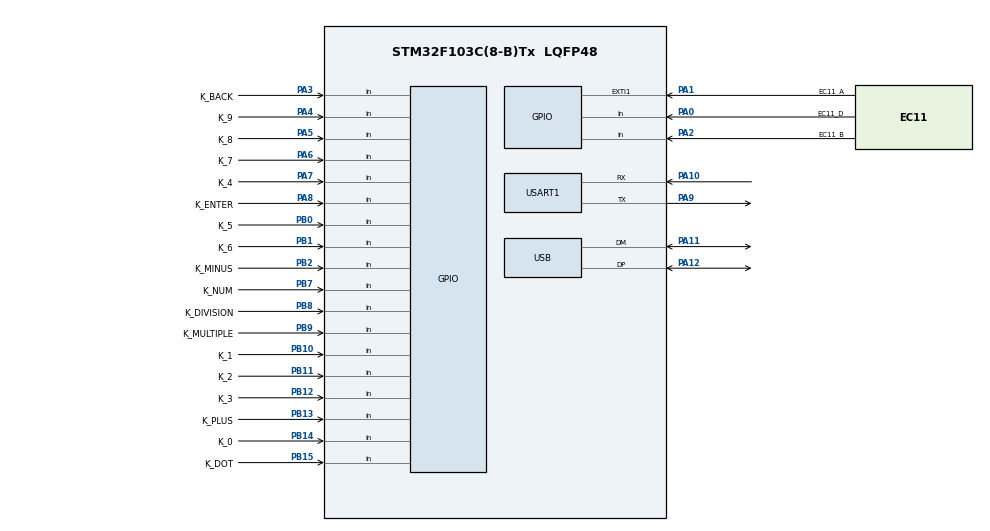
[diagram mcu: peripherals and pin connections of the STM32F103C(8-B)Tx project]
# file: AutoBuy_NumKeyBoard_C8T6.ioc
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Mcu.Family=STM32F1
Mcu.Name=STM32F103C(8-B)Tx
Mcu.Package=LQFP48
NVIC.PriorityGroup=NVIC_PRIORITYGROUP_4
NVIC.USART1_IRQn=true\:0\:0\:false\:false\:true\:true\:true\:true
NVIC.USB_LP_CAN1_RX0_IRQn=true\:0\:0\:false\:false\:true\:false\:true\:true
PA0-WKUP.GPIO_Label=EC11_D
PA0-WKUP.GPIO_PuPd=GPIO_PULLUP
PA0-WKUP.Signal=GPIO_Input
PA1.GPIO_Label=EC11_A
PA1.GPIO_ModeDefaultEXTI=GPIO_MODE_EVT_FALLING
PA1.GPIO_PuPd=GPIO_PULLUP
PA1.Signal=GPXTI1
PA10.Mode=Asynchronous
PA10.Signal=USART1_RX
PA11.Mode=Device
PA11.Signal=USB_DM
PA12.Mode=Device
PA12.Signal=USB_DP
PA13.Mode=Serial_Wire
PA13.Signal=SYS_JTMS-SWDIO
PA14.Mode=Serial_Wire
PA14.Signal=SYS_JTCK-SWCLK
PA2.GPIO_Label=EC11_B
PA2.Signal=GPIO_Input
PA3.GPIO_Label=K_BACK
PA3.GPIO_Mode=GPIO_MODE_INPUT
PA3.GPIO_PuPd=GPIO_NOPULL
PA3.Signal=GPIO_Input
PA4.GPIO_Label=K_9
PA4.GPIO_Mode=GPIO_MODE_INPUT
PA4.GPIO_PuPd=GPIO_NOPULL
PA4.Signal=GPIO_Input
PA5.GPIO_Label=K_8
PA5.GPIO_Mode=GPIO_MODE_INPUT
PA5.GPIO_PuPd=GPIO_NOPULL
PA5.Signal=GPIO_Input
PA6.GPIO_Label=K_7
PA6.GPIO_Mode=GPIO_MODE_INPUT
PA6.GPIO_PuPd=GPIO_NOPULL
PA6.Signal=GPIO_Input
PA7.GPIO_Label=K_4
PA7.GPIO_Mode=GPIO_MODE_INPUT
PA7.GPIO_PuPd=GPIO_NOPULL
PA7.Signal=GPIO_Input
PA8.GPIO_Label=K_ENTER
PA8.GPIO_Mode=GPIO_MODE_INPUT
PA8.GPIO_PuPd=GPIO_NOPULL
PA8.Signal=GPIO_Input
PA9.Mode=Asynchronous
PA9.Signal=USART1_TX
PB0.GPIO_Label=K_5
PB0.GPIO_Mode=GPIO_MODE_INPUT
PB0.GPIO_PuPd=GPIO_NOPULL
PB0.Signal=GPIO_Input
PB1.GPIO_Label=K_6
PB1.GPIO_Mode=GPIO_MODE_INPUT
PB1.GPIO_PuPd=GPIO_NOPULL
PB1.Signal=GPIO_Input
PB10.GPIO_Label=K_1
PB10.GPIO_Mode=GPIO_MODE_INPUT
PB10.GPIO_PuPd=GPIO_NOPULL
PB10.Signal=GPIO_Input
PB11.GPIO_Label=K_2
PB11.GPIO_Mode=GPIO_MODE_INPUT
PB11.GPIO_PuPd=GPIO_NOPULL
PB11.Signal=GPIO_Input
PB12.GPIO_Label=K_3
PB12.GPIO_Mode=GPIO_MODE_INPUT
PB12.GPIO_PuPd=GPIO_NOPULL
PB12.Signal=GPIO_Input
PB13.GPIO_Label=K_PLUS
PB13.GPIO_Mode=GPIO_MODE_INPUT
PB13.GPIO_PuPd=GPIO_NOPULL
PB13.Signal=GPIO_Input
PB14.GPIO_Label=K_0
PB14.GPIO_Mode=GPIO_MODE_INPUT
PB14.GPIO_PuPd=GPIO_PULLUP
PB14.Signal=GPIO_Input
PB15.GPIO_Label=K_DOT
PB15.GPIO_Mode=GPIO_MODE_INPUT
PB15.GPIO_PuPd=GPIO_PULLUP
PB15.Signal=GPIO_Input
PB2.GPIO_Label=K_MINUS
PB2.GPIO_Mode=GPIO_MODE_INPUT
PB2.GPIO_PuPd=GPIO_NOPULL
PB2.Signal=GPIO_Input
PB7.GPIO_Label=K_NUM
PB7.GPIO_Mode=GPIO_MODE_INPUT
PB7.GPIO_PuPd=GPIO_NOPULL
PB7.Signal=GPIO_Input
PB8.GPIO_Label=K_DIVISION
PB8.GPIO_Mode=GPIO_MODE_INPUT
PB8.GPIO_PuPd=GPIO_NOPULL
PB8.Signal=GPIO_Input
PB9.GPIO_Label=K_MULTIPLE
PB9.GPIO_Mode=GPIO_MODE_INPUT
PB9.GPIO_PuPd=GPIO_NOPULL
PB9.Signal=GPIO_Input
PD0-OSC_IN.Mode=HSE-External-Oscillator
PD0-OSC_IN.Signal=RCC_OSC_IN
PD1-OSC_OUT.Mode=HSE-External-Oscillator
PD1-OSC_OUT.Signal=RCC_OSC_OUT
ProjectManager.HeapSize=0x200
ProjectManager.StackSize=0x400
ProjectManager.TargetToolchain=Makefile
RCC.AHBFreq_Value=72000000
RCC.APB1CLKDivider=RCC_HCLK_DIV2
RCC.APB1Freq_Value=36000000
RCC.APB1TimFreq_Value=72000000
RCC.APB2Freq_Value=72000000
RCC.APB2TimFreq_Value=72000000
RCC.HCLKFreq_Value=72000000
RCC.HSE_VALUE=12000000
RCC.PLLMUL=RCC_PLL_MUL9
RCC.SYSCLKFreq_VALUE=72000000
RCC.SYSCLKSource=RCC_SYSCLKSOURCE_PLLCLK
RCC.USBFreq_Value=48000000
RCC.USBPrescaler=RCC_USBCLKSOURCE_PLL_DIV1_5
USART1.VirtualMode=VM_ASYNC
USB_DEVICE.CLASS_NAME_FS=HID
USB_DEVICE.VirtualMode=Hid
USB_DEVICE.VirtualModeFS=Hid_FS
VP_USB_DEVICE_VS_USB_DEVICE_HID_FS.Mode=HID_FS
board=custom

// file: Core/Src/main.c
/* USER CODE BEGIN Header */
/**
  ******************************************************************************
  * @file           : main.c
  * @brief          : Main program body
  ******************************************************************************
  * @attention
  *
  * Copyright (c) 2026 STMicroelectronics.
  * All rights reserved.
  *
  * This software is licensed under terms that can be found in the LICENSE file
  * in the root directory of this software component.
  * If no LICENSE file comes with this software, it is provided AS-IS.
  *
  ******************************************************************************
  */
/* USER CODE END Header */
#include "main.h"
#include "usart.h"
#include "usb_device.h"
#include "gpio.h"

/* USER CODE BEGIN Includes */
#include "stdbool.h"
#include "stdint.h"
#include "referee_protocol.h"
#include "referee_frame_process.h"
#include "app_keyboard.h"
#include "app_ec11.h"
#include "bsp_ec11.h"
/* USER CODE END Includes */

/* USER CODE BEGIN PD */
#define NUM_KEYS 3
#define DELAY_MS 25
/* USER CODE END PD */

void SystemClock_Config(void);

int main(void)
{

  /* MCU Configuration--------------------------------------------------------*/

  /* Reset of all peripherals, Initializes the Flash interface and the Systick. */
  HAL_Init();

  /* Configure the system clock */
  SystemClock_Config();

  /* Initialize all configured peripherals */
  MX_GPIO_Init();
  MX_USART1_UART_Init();
  MX_USB_DEVICE_Init();
  /* USER CODE BEGIN 2 */
  appKeyboardInit();
  appEc11Init();
  appMacroInit();
  /* USER CODE END 2 */

  /* Infinite loop */
  while (1)
  {

    /* USER CODE BEGIN 3 */
    if (__HAL_UART_GET_FLAG(&huart1, UART_FLAG_ORE) != RESET)
    {
      __HAL_UART_CLEAR_OREFLAG(&huart1);
    }

    int32_t ec11_count = appEc11GetCount();
    Ec11ButtonState btn_state = appEc11GetButtonState();

    appKeyboardUpdate();
    appMacroUpdate();
  }
  /* USER CODE END 3 */
}

void SystemClock_Config(void)
{
  RCC_OscInitTypeDef RCC_OscInitStruct = {0};
  RCC_ClkInitTypeDef RCC_ClkInitStruct = {0};
  RCC_PeriphCLKInitTypeDef PeriphClkInit = {0};

  /** Initializes the RCC Oscillators according to the specified parameters
  * in the RCC_OscInitTypeDef structure.
  */
  RCC_OscInitStruct.OscillatorType = RCC_OSCILLATORTYPE_HSE;
  RCC_OscInitStruct.HSEState = RCC_HSE_ON;
  RCC_OscInitStruct.HSEPredivValue = RCC_HSE_PREDIV_DIV1;
  RCC_OscInitStruct.HSIState = RCC_HSI_ON;
  RCC_OscInitStruct.PLL.PLLState = RCC_PLL_ON;
  RCC_OscInitStruct.PLL.PLLSource = RCC_PLLSOURCE_HSE;
  RCC_OscInitStruct.PLL.PLLMUL = RCC_PLL_MUL9;
  if (HAL_RCC_OscConfig(&RCC_OscInitStruct) != HAL_OK)
  {
    Error_Handler();
  }

  /** Initializes the CPU, AHB and APB buses clocks
  */
  RCC_ClkInitStruct.ClockType = RCC_CLOCKTYPE_HCLK|RCC_CLOCKTYPE_SYSCLK
                              |RCC_CLOCKTYPE_PCLK1|RCC_CLOCKTYPE_PCLK2;
  RCC_ClkInitStruct.SYSCLKSource = RCC_SYSCLKSOURCE_PLLCLK;
  RCC_ClkInitStruct.AHBCLKDivider = RCC_SYSCLK_DIV1;
  RCC_ClkInitStruct.APB1CLKDivider = RCC_HCLK_DIV2;
  RCC_ClkInitStruct.APB2CLKDivider = RCC_HCLK_DIV1;

  if (HAL_RCC_ClockConfig(&RCC_ClkInitStruct, FLASH_LATENCY_2) != HAL_OK)
  {
    Error_Handler();
  }
  PeriphClkInit.PeriphClockSelection = RCC_PERIPHCLK_USB;
  PeriphClkInit.UsbClockSelection = RCC_USBCLKSOURCE_PLL_DIV1_5;
  if (HAL_RCCEx_PeriphCLKConfig(&PeriphClkInit) != HAL_OK)
  {
    Error_Handler();
  }
}

/* USER CODE BEGIN 4 */
void HAL_GPIO_EXTI_Callback(uint16_t GPIO_Pin)
{
  appEc11ExtiCallback(GPIO_Pin);
}
/* USER CODE END 4 */

void Error_Handler(void)
{
  __disable_irq();
  while (1)
  {
  }
}
